VERSION 5.7 ;
BUSBITCHARS "[]" ;
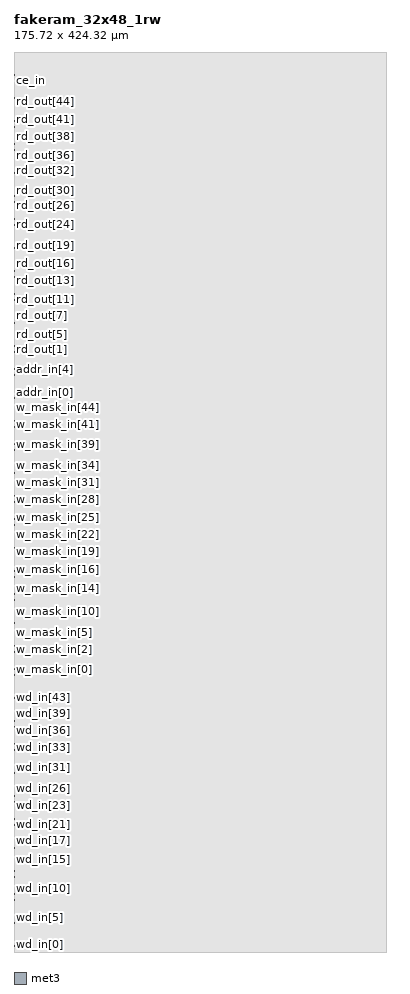
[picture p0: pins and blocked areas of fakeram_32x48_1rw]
MACRO fakeram_32x48_1rw
  FOREIGN fakeram_32x48_1rw 0 0 ;
  SYMMETRY X Y R90 ;
  SIZE 175.720 BY 424.320 ;
  CLASS BLOCK ;
  PIN wd_in[0]
    DIRECTION INPUT ;
    USE SIGNAL ;
    SHAPE ABUTMENT ;
    PORT
      LAYER met3 ;
      RECT 0.000 2.720 0.170 2.890 ;
    END
  END wd_in[0]
  PIN wd_in[1]
    DIRECTION INPUT ;
    USE SIGNAL ;
    SHAPE ABUTMENT ;
    PORT
      LAYER met3 ;
      RECT 0.000 5.440 0.170 5.610 ;
    END
  END wd_in[1]
  PIN wd_in[2]
    DIRECTION INPUT ;
    USE SIGNAL ;
    SHAPE ABUTMENT ;
    PORT
      LAYER met3 ;
      RECT 0.000 8.160 0.170 8.330 ;
    END
  END wd_in[2]
  PIN wd_in[3]
    DIRECTION INPUT ;
    USE SIGNAL ;
    SHAPE ABUTMENT ;
    PORT
      LAYER met3 ;
      RECT 0.000 10.880 0.170 11.050 ;
    END
  END wd_in[3]
  PIN wd_in[4]
    DIRECTION INPUT ;
    USE SIGNAL ;
    SHAPE ABUTMENT ;
    PORT
      LAYER met3 ;
      RECT 0.000 13.600 0.170 13.770 ;
    END
  END wd_in[4]
  PIN wd_in[5]
    DIRECTION INPUT ;
    USE SIGNAL ;
    SHAPE ABUTMENT ;
    PORT
      LAYER met3 ;
      RECT 0.000 16.320 0.170 16.490 ;
    END
  END wd_in[5]
  PIN wd_in[6]
    DIRECTION INPUT ;
    USE SIGNAL ;
    SHAPE ABUTMENT ;
    PORT
      LAYER met3 ;
      RECT 0.000 19.040 0.170 19.210 ;
    END
  END wd_in[6]
  PIN wd_in[7]
    DIRECTION INPUT ;
    USE SIGNAL ;
    SHAPE ABUTMENT ;
    PORT
      LAYER met3 ;
      RECT 0.000 21.760 0.170 21.930 ;
    END
  END wd_in[7]
  PIN wd_in[8]
    DIRECTION INPUT ;
    USE SIGNAL ;
    SHAPE ABUTMENT ;
    PORT
      LAYER met3 ;
      RECT 0.000 24.480 0.170 24.650 ;
    END
  END wd_in[8]
  PIN wd_in[9]
    DIRECTION INPUT ;
    USE SIGNAL ;
    SHAPE ABUTMENT ;
    PORT
      LAYER met3 ;
      RECT 0.000 27.200 0.170 27.370 ;
    END
  END wd_in[9]
  PIN wd_in[10]
    DIRECTION INPUT ;
    USE SIGNAL ;
    SHAPE ABUTMENT ;
    PORT
      LAYER met3 ;
      RECT 0.000 29.920 0.170 30.090 ;
    END
  END wd_in[10]
  PIN wd_in[11]
    DIRECTION INPUT ;
    USE SIGNAL ;
    SHAPE ABUTMENT ;
    PORT
      LAYER met3 ;
      RECT 0.000 32.640 0.170 32.810 ;
    END
  END wd_in[11]
  PIN wd_in[12]
    DIRECTION INPUT ;
    USE SIGNAL ;
    SHAPE ABUTMENT ;
    PORT
      LAYER met3 ;
      RECT 0.000 35.360 0.170 35.530 ;
    END
  END wd_in[12]
  PIN wd_in[13]
    DIRECTION INPUT ;
    USE SIGNAL ;
    SHAPE ABUTMENT ;
    PORT
      LAYER met3 ;
      RECT 0.000 38.080 0.170 38.250 ;
    END
  END wd_in[13]
  PIN wd_in[14]
    DIRECTION INPUT ;
    USE SIGNAL ;
    SHAPE ABUTMENT ;
    PORT
      LAYER met3 ;
      RECT 0.000 40.800 0.170 40.970 ;
    END
  END wd_in[14]
  PIN wd_in[15]
    DIRECTION INPUT ;
    USE SIGNAL ;
    SHAPE ABUTMENT ;
    PORT
      LAYER met3 ;
      RECT 0.000 43.520 0.170 43.690 ;
    END
  END wd_in[15]
  PIN wd_in[16]
    DIRECTION INPUT ;
    USE SIGNAL ;
    SHAPE ABUTMENT ;
    PORT
      LAYER met3 ;
      RECT 0.000 46.240 0.170 46.410 ;
    END
  END wd_in[16]
  PIN wd_in[17]
    DIRECTION INPUT ;
    USE SIGNAL ;
    SHAPE ABUTMENT ;
    PORT
      LAYER met3 ;
      RECT 0.000 48.960 0.170 49.130 ;
    END
  END wd_in[17]
  PIN wd_in[18]
    DIRECTION INPUT ;
    USE SIGNAL ;
    SHAPE ABUTMENT ;
    PORT
      LAYER met3 ;
      RECT 0.000 51.680 0.170 51.850 ;
    END
  END wd_in[18]
  PIN wd_in[19]
    DIRECTION INPUT ;
    USE SIGNAL ;
    SHAPE ABUTMENT ;
    PORT
      LAYER met3 ;
      RECT 0.000 54.400 0.170 54.570 ;
    END
  END wd_in[19]
  PIN wd_in[20]
    DIRECTION INPUT ;
    USE SIGNAL ;
    SHAPE ABUTMENT ;
    PORT
      LAYER met3 ;
      RECT 0.000 57.120 0.170 57.290 ;
    END
  END wd_in[20]
  PIN wd_in[21]
    DIRECTION INPUT ;
    USE SIGNAL ;
    SHAPE ABUTMENT ;
    PORT
      LAYER met3 ;
      RECT 0.000 59.840 0.170 60.010 ;
    END
  END wd_in[21]
  PIN wd_in[22]
    DIRECTION INPUT ;
    USE SIGNAL ;
    SHAPE ABUTMENT ;
    PORT
      LAYER met3 ;
      RECT 0.000 62.560 0.170 62.730 ;
    END
  END wd_in[22]
  PIN wd_in[23]
    DIRECTION INPUT ;
    USE SIGNAL ;
    SHAPE ABUTMENT ;
    PORT
      LAYER met3 ;
      RECT 0.000 65.280 0.170 65.450 ;
    END
  END wd_in[23]
  PIN wd_in[24]
    DIRECTION INPUT ;
    USE SIGNAL ;
    SHAPE ABUTMENT ;
    PORT
      LAYER met3 ;
      RECT 0.000 68.000 0.170 68.170 ;
    END
  END wd_in[24]
  PIN wd_in[25]
    DIRECTION INPUT ;
    USE SIGNAL ;
    SHAPE ABUTMENT ;
    PORT
      LAYER met3 ;
      RECT 0.000 70.720 0.170 70.890 ;
    END
  END wd_in[25]
  PIN wd_in[26]
    DIRECTION INPUT ;
    USE SIGNAL ;
    SHAPE ABUTMENT ;
    PORT
      LAYER met3 ;
      RECT 0.000 73.440 0.170 73.610 ;
    END
  END wd_in[26]
  PIN wd_in[27]
    DIRECTION INPUT ;
    USE SIGNAL ;
    SHAPE ABUTMENT ;
    PORT
      LAYER met3 ;
      RECT 0.000 76.160 0.170 76.330 ;
    END
  END wd_in[27]
  PIN wd_in[28]
    DIRECTION INPUT ;
    USE SIGNAL ;
    SHAPE ABUTMENT ;
    PORT
      LAYER met3 ;
      RECT 0.000 78.880 0.170 79.050 ;
    END
  END wd_in[28]
  PIN wd_in[29]
    DIRECTION INPUT ;
    USE SIGNAL ;
    SHAPE ABUTMENT ;
    PORT
      LAYER met3 ;
      RECT 0.000 81.600 0.170 81.770 ;
    END
  END wd_in[29]
  PIN wd_in[30]
    DIRECTION INPUT ;
    USE SIGNAL ;
    SHAPE ABUTMENT ;
    PORT
      LAYER met3 ;
      RECT 0.000 84.320 0.170 84.490 ;
    END
  END wd_in[30]
  PIN wd_in[31]
    DIRECTION INPUT ;
    USE SIGNAL ;
    SHAPE ABUTMENT ;
    PORT
      LAYER met3 ;
      RECT 0.000 87.040 0.170 87.210 ;
    END
  END wd_in[31]
  PIN wd_in[32]
    DIRECTION INPUT ;
    USE SIGNAL ;
    SHAPE ABUTMENT ;
    PORT
      LAYER met3 ;
      RECT 0.000 89.760 0.170 89.930 ;
    END
  END wd_in[32]
  PIN wd_in[33]
    DIRECTION INPUT ;
    USE SIGNAL ;
    SHAPE ABUTMENT ;
    PORT
      LAYER met3 ;
      RECT 0.000 92.480 0.170 92.650 ;
    END
  END wd_in[33]
  PIN wd_in[34]
    DIRECTION INPUT ;
    USE SIGNAL ;
    SHAPE ABUTMENT ;
    PORT
      LAYER met3 ;
      RECT 0.000 95.200 0.170 95.370 ;
    END
  END wd_in[34]
  PIN wd_in[35]
    DIRECTION INPUT ;
    USE SIGNAL ;
    SHAPE ABUTMENT ;
    PORT
      LAYER met3 ;
      RECT 0.000 97.920 0.170 98.090 ;
    END
  END wd_in[35]
  PIN wd_in[36]
    DIRECTION INPUT ;
    USE SIGNAL ;
    SHAPE ABUTMENT ;
    PORT
      LAYER met3 ;
      RECT 0.000 100.640 0.170 100.810 ;
    END
  END wd_in[36]
  PIN wd_in[37]
    DIRECTION INPUT ;
    USE SIGNAL ;
    SHAPE ABUTMENT ;
    PORT
      LAYER met3 ;
      RECT 0.000 103.360 0.170 103.530 ;
    END
  END wd_in[37]
  PIN wd_in[38]
    DIRECTION INPUT ;
    USE SIGNAL ;
    SHAPE ABUTMENT ;
    PORT
      LAYER met3 ;
      RECT 0.000 106.080 0.170 106.250 ;
    END
  END wd_in[38]
  PIN wd_in[39]
    DIRECTION INPUT ;
    USE SIGNAL ;
    SHAPE ABUTMENT ;
    PORT
      LAYER met3 ;
      RECT 0.000 108.800 0.170 108.970 ;
    END
  END wd_in[39]
  PIN wd_in[40]
    DIRECTION INPUT ;
    USE SIGNAL ;
    SHAPE ABUTMENT ;
    PORT
      LAYER met3 ;
      RECT 0.000 111.520 0.170 111.690 ;
    END
  END wd_in[40]
  PIN wd_in[41]
    DIRECTION INPUT ;
    USE SIGNAL ;
    SHAPE ABUTMENT ;
    PORT
      LAYER met3 ;
      RECT 0.000 114.240 0.170 114.410 ;
    END
  END wd_in[41]
  PIN wd_in[42]
    DIRECTION INPUT ;
    USE SIGNAL ;
    SHAPE ABUTMENT ;
    PORT
      LAYER met3 ;
      RECT 0.000 116.960 0.170 117.130 ;
    END
  END wd_in[42]
  PIN wd_in[43]
    DIRECTION INPUT ;
    USE SIGNAL ;
    SHAPE ABUTMENT ;
    PORT
      LAYER met3 ;
      RECT 0.000 119.680 0.170 119.850 ;
    END
  END wd_in[43]
  PIN wd_in[44]
    DIRECTION INPUT ;
    USE SIGNAL ;
    SHAPE ABUTMENT ;
    PORT
      LAYER met3 ;
      RECT 0.000 122.400 0.170 122.570 ;
    END
  END wd_in[44]
  PIN wd_in[45]
    DIRECTION INPUT ;
    USE SIGNAL ;
    SHAPE ABUTMENT ;
    PORT
      LAYER met3 ;
      RECT 0.000 125.120 0.170 125.290 ;
    END
  END wd_in[45]
  PIN wd_in[46]
    DIRECTION INPUT ;
    USE SIGNAL ;
    SHAPE ABUTMENT ;
    PORT
      LAYER met3 ;
      RECT 0.000 127.840 0.170 128.010 ;
    END
  END wd_in[46]
  PIN wd_in[47]
    DIRECTION INPUT ;
    USE SIGNAL ;
    SHAPE ABUTMENT ;
    PORT
      LAYER met3 ;
      RECT 0.000 130.560 0.170 130.730 ;
    END
  END wd_in[47]
  PIN w_mask_in[0]
    DIRECTION INPUT ;
    USE SIGNAL ;
    SHAPE ABUTMENT ;
    PORT
      LAYER met3 ;
      RECT 0.000 133.280 0.170 133.450 ;
    END
  END w_mask_in[0]
  PIN w_mask_in[1]
    DIRECTION INPUT ;
    USE SIGNAL ;
    SHAPE ABUTMENT ;
    PORT
      LAYER met3 ;
      RECT 0.000 136.000 0.170 136.170 ;
    END
  END w_mask_in[1]
  PIN w_mask_in[2]
    DIRECTION INPUT ;
    USE SIGNAL ;
    SHAPE ABUTMENT ;
    PORT
      LAYER met3 ;
      RECT 0.000 138.720 0.170 138.890 ;
    END
  END w_mask_in[2]
  PIN w_mask_in[3]
    DIRECTION INPUT ;
    USE SIGNAL ;
    SHAPE ABUTMENT ;
    PORT
      LAYER met3 ;
      RECT 0.000 141.440 0.170 141.610 ;
    END
  END w_mask_in[3]
  PIN w_mask_in[4]
    DIRECTION INPUT ;
    USE SIGNAL ;
    SHAPE ABUTMENT ;
    PORT
      LAYER met3 ;
      RECT 0.000 144.160 0.170 144.330 ;
    END
  END w_mask_in[4]
  PIN w_mask_in[5]
    DIRECTION INPUT ;
    USE SIGNAL ;
    SHAPE ABUTMENT ;
    PORT
      LAYER met3 ;
      RECT 0.000 146.880 0.170 147.050 ;
    END
  END w_mask_in[5]
  PIN w_mask_in[6]
    DIRECTION INPUT ;
    USE SIGNAL ;
    SHAPE ABUTMENT ;
    PORT
      LAYER met3 ;
      RECT 0.000 149.600 0.170 149.770 ;
    END
  END w_mask_in[6]
  PIN w_mask_in[7]
    DIRECTION INPUT ;
    USE SIGNAL ;
    SHAPE ABUTMENT ;
    PORT
      LAYER met3 ;
      RECT 0.000 152.320 0.170 152.490 ;
    END
  END w_mask_in[7]
  PIN w_mask_in[8]
    DIRECTION INPUT ;
    USE SIGNAL ;
    SHAPE ABUTMENT ;
    PORT
      LAYER met3 ;
      RECT 0.000 155.040 0.170 155.210 ;
    END
  END w_mask_in[8]
  PIN w_mask_in[9]
    DIRECTION INPUT ;
    USE SIGNAL ;
    SHAPE ABUTMENT ;
    PORT
      LAYER met3 ;
      RECT 0.000 157.760 0.170 157.930 ;
    END
  END w_mask_in[9]
  PIN w_mask_in[10]
    DIRECTION INPUT ;
    USE SIGNAL ;
    SHAPE ABUTMENT ;
    PORT
      LAYER met3 ;
      RECT 0.000 160.480 0.170 160.650 ;
    END
  END w_mask_in[10]
  PIN w_mask_in[11]
    DIRECTION INPUT ;
    USE SIGNAL ;
    SHAPE ABUTMENT ;
    PORT
      LAYER met3 ;
      RECT 0.000 163.200 0.170 163.370 ;
    END
  END w_mask_in[11]
  PIN w_mask_in[12]
    DIRECTION INPUT ;
    USE SIGNAL ;
    SHAPE ABUTMENT ;
    PORT
      LAYER met3 ;
      RECT 0.000 165.920 0.170 166.090 ;
    END
  END w_mask_in[12]
  PIN w_mask_in[13]
    DIRECTION INPUT ;
    USE SIGNAL ;
    SHAPE ABUTMENT ;
    PORT
      LAYER met3 ;
      RECT 0.000 168.640 0.170 168.810 ;
    END
  END w_mask_in[13]
  PIN w_mask_in[14]
    DIRECTION INPUT ;
    USE SIGNAL ;
    SHAPE ABUTMENT ;
    PORT
      LAYER met3 ;
      RECT 0.000 171.360 0.170 171.530 ;
    END
  END w_mask_in[14]
  PIN w_mask_in[15]
    DIRECTION INPUT ;
    USE SIGNAL ;
    SHAPE ABUTMENT ;
    PORT
      LAYER met3 ;
      RECT 0.000 174.080 0.170 174.250 ;
    END
  END w_mask_in[15]
  PIN w_mask_in[16]
    DIRECTION INPUT ;
    USE SIGNAL ;
    SHAPE ABUTMENT ;
    PORT
      LAYER met3 ;
      RECT 0.000 176.800 0.170 176.970 ;
    END
  END w_mask_in[16]
  PIN w_mask_in[17]
    DIRECTION INPUT ;
    USE SIGNAL ;
    SHAPE ABUTMENT ;
    PORT
      LAYER met3 ;
      RECT 0.000 179.520 0.170 179.690 ;
    END
  END w_mask_in[17]
  PIN w_mask_in[18]
    DIRECTION INPUT ;
    USE SIGNAL ;
    SHAPE ABUTMENT ;
    PORT
      LAYER met3 ;
      RECT 0.000 182.240 0.170 182.410 ;
    END
  END w_mask_in[18]
  PIN w_mask_in[19]
    DIRECTION INPUT ;
    USE SIGNAL ;
    SHAPE ABUTMENT ;
    PORT
      LAYER met3 ;
      RECT 0.000 184.960 0.170 185.130 ;
    END
  END w_mask_in[19]
  PIN w_mask_in[20]
    DIRECTION INPUT ;
    USE SIGNAL ;
    SHAPE ABUTMENT ;
    PORT
      LAYER met3 ;
      RECT 0.000 187.680 0.170 187.850 ;
    END
  END w_mask_in[20]
  PIN w_mask_in[21]
    DIRECTION INPUT ;
    USE SIGNAL ;
    SHAPE ABUTMENT ;
    PORT
      LAYER met3 ;
      RECT 0.000 190.400 0.170 190.570 ;
    END
  END w_mask_in[21]
  PIN w_mask_in[22]
    DIRECTION INPUT ;
    USE SIGNAL ;
    SHAPE ABUTMENT ;
    PORT
      LAYER met3 ;
      RECT 0.000 193.120 0.170 193.290 ;
    END
  END w_mask_in[22]
  PIN w_mask_in[23]
    DIRECTION INPUT ;
    USE SIGNAL ;
    SHAPE ABUTMENT ;
    PORT
      LAYER met3 ;
      RECT 0.000 195.840 0.170 196.010 ;
    END
  END w_mask_in[23]
  PIN w_mask_in[24]
    DIRECTION INPUT ;
    USE SIGNAL ;
    SHAPE ABUTMENT ;
    PORT
      LAYER met3 ;
      RECT 0.000 198.560 0.170 198.730 ;
    END
  END w_mask_in[24]
  PIN w_mask_in[25]
    DIRECTION INPUT ;
    USE SIGNAL ;
    SHAPE ABUTMENT ;
    PORT
      LAYER met3 ;
      RECT 0.000 201.280 0.170 201.450 ;
    END
  END w_mask_in[25]
  PIN w_mask_in[26]
    DIRECTION INPUT ;
    USE SIGNAL ;
    SHAPE ABUTMENT ;
    PORT
      LAYER met3 ;
      RECT 0.000 204.000 0.170 204.170 ;
    END
  END w_mask_in[26]
  PIN w_mask_in[27]
    DIRECTION INPUT ;
    USE SIGNAL ;
    SHAPE ABUTMENT ;
    PORT
      LAYER met3 ;
      RECT 0.000 206.720 0.170 206.890 ;
    END
  END w_mask_in[27]
  PIN w_mask_in[28]
    DIRECTION INPUT ;
    USE SIGNAL ;
    SHAPE ABUTMENT ;
    PORT
      LAYER met3 ;
      RECT 0.000 209.440 0.170 209.610 ;
    END
  END w_mask_in[28]
  PIN w_mask_in[29]
    DIRECTION INPUT ;
    USE SIGNAL ;
    SHAPE ABUTMENT ;
    PORT
      LAYER met3 ;
      RECT 0.000 212.160 0.170 212.330 ;
    END
  END w_mask_in[29]
  PIN w_mask_in[30]
    DIRECTION INPUT ;
    USE SIGNAL ;
    SHAPE ABUTMENT ;
    PORT
      LAYER met3 ;
      RECT 0.000 214.880 0.170 215.050 ;
    END
  END w_mask_in[30]
  PIN w_mask_in[31]
    DIRECTION INPUT ;
    USE SIGNAL ;
    SHAPE ABUTMENT ;
    PORT
      LAYER met3 ;
      RECT 0.000 217.600 0.170 217.770 ;
    END
  END w_mask_in[31]
  PIN w_mask_in[32]
    DIRECTION INPUT ;
    USE SIGNAL ;
    SHAPE ABUTMENT ;
    PORT
      LAYER met3 ;
      RECT 0.000 220.320 0.170 220.490 ;
    END
  END w_mask_in[32]
  PIN w_mask_in[33]
    DIRECTION INPUT ;
    USE SIGNAL ;
    SHAPE ABUTMENT ;
    PORT
      LAYER met3 ;
      RECT 0.000 223.040 0.170 223.210 ;
    END
  END w_mask_in[33]
  PIN w_mask_in[34]
    DIRECTION INPUT ;
    USE SIGNAL ;
    SHAPE ABUTMENT ;
    PORT
      LAYER met3 ;
      RECT 0.000 225.760 0.170 225.930 ;
    END
  END w_mask_in[34]
  PIN w_mask_in[35]
    DIRECTION INPUT ;
    USE SIGNAL ;
    SHAPE ABUTMENT ;
    PORT
      LAYER met3 ;
      RECT 0.000 228.480 0.170 228.650 ;
    END
  END w_mask_in[35]
  PIN w_mask_in[36]
    DIRECTION INPUT ;
    USE SIGNAL ;
    SHAPE ABUTMENT ;
    PORT
      LAYER met3 ;
      RECT 0.000 231.200 0.170 231.370 ;
    END
  END w_mask_in[36]
  PIN w_mask_in[37]
    DIRECTION INPUT ;
    USE SIGNAL ;
    SHAPE ABUTMENT ;
    PORT
      LAYER met3 ;
      RECT 0.000 233.920 0.170 234.090 ;
    END
  END w_mask_in[37]
  PIN w_mask_in[38]
    DIRECTION INPUT ;
    USE SIGNAL ;
    SHAPE ABUTMENT ;
    PORT
      LAYER met3 ;
      RECT 0.000 236.640 0.170 236.810 ;
    END
  END w_mask_in[38]
  PIN w_mask_in[39]
    DIRECTION INPUT ;
    USE SIGNAL ;
    SHAPE ABUTMENT ;
    PORT
      LAYER met3 ;
      RECT 0.000 239.360 0.170 239.530 ;
    END
  END w_mask_in[39]
  PIN w_mask_in[40]
    DIRECTION INPUT ;
    USE SIGNAL ;
    SHAPE ABUTMENT ;
    PORT
      LAYER met3 ;
      RECT 0.000 242.080 0.170 242.250 ;
    END
  END w_mask_in[40]
  PIN w_mask_in[41]
    DIRECTION INPUT ;
    USE SIGNAL ;
    SHAPE ABUTMENT ;
    PORT
      LAYER met3 ;
      RECT 0.000 244.800 0.170 244.970 ;
    END
  END w_mask_in[41]
  PIN w_mask_in[42]
    DIRECTION INPUT ;
    USE SIGNAL ;
    SHAPE ABUTMENT ;
    PORT
      LAYER met3 ;
      RECT 0.000 247.520 0.170 247.690 ;
    END
  END w_mask_in[42]
  PIN w_mask_in[43]
    DIRECTION INPUT ;
    USE SIGNAL ;
    SHAPE ABUTMENT ;
    PORT
      LAYER met3 ;
      RECT 0.000 250.240 0.170 250.410 ;
    END
  END w_mask_in[43]
  PIN w_mask_in[44]
    DIRECTION INPUT ;
    USE SIGNAL ;
    SHAPE ABUTMENT ;
    PORT
      LAYER met3 ;
      RECT 0.000 252.960 0.170 253.130 ;
    END
  END w_mask_in[44]
  PIN w_mask_in[45]
    DIRECTION INPUT ;
    USE SIGNAL ;
    SHAPE ABUTMENT ;
    PORT
      LAYER met3 ;
      RECT 0.000 255.680 0.170 255.850 ;
    END
  END w_mask_in[45]
  PIN w_mask_in[46]
    DIRECTION INPUT ;
    USE SIGNAL ;
    SHAPE ABUTMENT ;
    PORT
      LAYER met3 ;
      RECT 0.000 258.400 0.170 258.570 ;
    END
  END w_mask_in[46]
  PIN w_mask_in[47]
    DIRECTION INPUT ;
    USE SIGNAL ;
    SHAPE ABUTMENT ;
    PORT
      LAYER met3 ;
      RECT 0.000 261.120 0.170 261.290 ;
    END
  END w_mask_in[47]
  PIN addr_in[0]
    DIRECTION INPUT ;
    USE SIGNAL ;
    SHAPE ABUTMENT ;
    PORT
      LAYER met3 ;
      RECT 0.000 263.840 0.170 264.010 ;
    END
  END addr_in[0]
  PIN addr_in[1]
    DIRECTION INPUT ;
    USE SIGNAL ;
    SHAPE ABUTMENT ;
    PORT
      LAYER met3 ;
      RECT 0.000 266.560 0.170 266.730 ;
    END
  END addr_in[1]
  PIN addr_in[2]
    DIRECTION INPUT ;
    USE SIGNAL ;
    SHAPE ABUTMENT ;
    PORT
      LAYER met3 ;
      RECT 0.000 269.280 0.170 269.450 ;
    END
  END addr_in[2]
  PIN addr_in[3]
    DIRECTION INPUT ;
    USE SIGNAL ;
    SHAPE ABUTMENT ;
    PORT
      LAYER met3 ;
      RECT 0.000 272.000 0.170 272.170 ;
    END
  END addr_in[3]
  PIN addr_in[4]
    DIRECTION INPUT ;
    USE SIGNAL ;
    SHAPE ABUTMENT ;
    PORT
      LAYER met3 ;
      RECT 0.000 274.720 0.170 274.890 ;
    END
  END addr_in[4]
  PIN rd_out[0]
    DIRECTION OUTPUT ;
    USE SIGNAL ;
    SHAPE ABUTMENT ;
    PORT
      LAYER met3 ;
      RECT 0.000 277.440 0.170 277.610 ;
    END
  END rd_out[0]
  PIN rd_out[1]
    DIRECTION OUTPUT ;
    USE SIGNAL ;
    SHAPE ABUTMENT ;
    PORT
      LAYER met3 ;
      RECT 0.000 280.160 0.170 280.330 ;
    END
  END rd_out[1]
  PIN rd_out[2]
    DIRECTION OUTPUT ;
    USE SIGNAL ;
    SHAPE ABUTMENT ;
    PORT
      LAYER met3 ;
      RECT 0.000 282.880 0.170 283.050 ;
    END
  END rd_out[2]
  PIN rd_out[3]
    DIRECTION OUTPUT ;
    USE SIGNAL ;
    SHAPE ABUTMENT ;
    PORT
      LAYER met3 ;
      RECT 0.000 285.600 0.170 285.770 ;
    END
  END rd_out[3]
  PIN rd_out[4]
    DIRECTION OUTPUT ;
    USE SIGNAL ;
    SHAPE ABUTMENT ;
    PORT
      LAYER met3 ;
      RECT 0.000 288.320 0.170 288.490 ;
    END
  END rd_out[4]
  PIN rd_out[5]
    DIRECTION OUTPUT ;
    USE SIGNAL ;
    SHAPE ABUTMENT ;
    PORT
      LAYER met3 ;
      RECT 0.000 291.040 0.170 291.210 ;
    END
  END rd_out[5]
  PIN rd_out[6]
    DIRECTION OUTPUT ;
    USE SIGNAL ;
    SHAPE ABUTMENT ;
    PORT
      LAYER met3 ;
      RECT 0.000 293.760 0.170 293.930 ;
    END
  END rd_out[6]
  PIN rd_out[7]
    DIRECTION OUTPUT ;
    USE SIGNAL ;
    SHAPE ABUTMENT ;
    PORT
      LAYER met3 ;
      RECT 0.000 296.480 0.170 296.650 ;
    END
  END rd_out[7]
  PIN rd_out[8]
    DIRECTION OUTPUT ;
    USE SIGNAL ;
    SHAPE ABUTMENT ;
    PORT
      LAYER met3 ;
      RECT 0.000 299.200 0.170 299.370 ;
    END
  END rd_out[8]
  PIN rd_out[9]
    DIRECTION OUTPUT ;
    USE SIGNAL ;
    SHAPE ABUTMENT ;
    PORT
      LAYER met3 ;
      RECT 0.000 301.920 0.170 302.090 ;
    END
  END rd_out[9]
  PIN rd_out[10]
    DIRECTION OUTPUT ;
    USE SIGNAL ;
    SHAPE ABUTMENT ;
    PORT
      LAYER met3 ;
      RECT 0.000 304.640 0.170 304.810 ;
    END
  END rd_out[10]
  PIN rd_out[11]
    DIRECTION OUTPUT ;
    USE SIGNAL ;
    SHAPE ABUTMENT ;
    PORT
      LAYER met3 ;
      RECT 0.000 307.360 0.170 307.530 ;
    END
  END rd_out[11]
  PIN rd_out[12]
    DIRECTION OUTPUT ;
    USE SIGNAL ;
    SHAPE ABUTMENT ;
    PORT
      LAYER met3 ;
      RECT 0.000 310.080 0.170 310.250 ;
    END
  END rd_out[12]
  PIN rd_out[13]
    DIRECTION OUTPUT ;
    USE SIGNAL ;
    SHAPE ABUTMENT ;
    PORT
      LAYER met3 ;
      RECT 0.000 312.800 0.170 312.970 ;
    END
  END rd_out[13]
  PIN rd_out[14]
    DIRECTION OUTPUT ;
    USE SIGNAL ;
    SHAPE ABUTMENT ;
    PORT
      LAYER met3 ;
      RECT 0.000 315.520 0.170 315.690 ;
    END
  END rd_out[14]
  PIN rd_out[15]
    DIRECTION OUTPUT ;
    USE SIGNAL ;
    SHAPE ABUTMENT ;
    PORT
      LAYER met3 ;
      RECT 0.000 318.240 0.170 318.410 ;
    END
  END rd_out[15]
  PIN rd_out[16]
    DIRECTION OUTPUT ;
    USE SIGNAL ;
    SHAPE ABUTMENT ;
    PORT
      LAYER met3 ;
      RECT 0.000 320.960 0.170 321.130 ;
    END
  END rd_out[16]
  PIN rd_out[17]
    DIRECTION OUTPUT ;
    USE SIGNAL ;
    SHAPE ABUTMENT ;
    PORT
      LAYER met3 ;
      RECT 0.000 323.680 0.170 323.850 ;
    END
  END rd_out[17]
  PIN rd_out[18]
    DIRECTION OUTPUT ;
    USE SIGNAL ;
    SHAPE ABUTMENT ;
    PORT
      LAYER met3 ;
      RECT 0.000 326.400 0.170 326.570 ;
    END
  END rd_out[18]
  PIN rd_out[19]
    DIRECTION OUTPUT ;
    USE SIGNAL ;
    SHAPE ABUTMENT ;
    PORT
      LAYER met3 ;
      RECT 0.000 329.120 0.170 329.290 ;
    END
  END rd_out[19]
  PIN rd_out[20]
    DIRECTION OUTPUT ;
    USE SIGNAL ;
    SHAPE ABUTMENT ;
    PORT
      LAYER met3 ;
      RECT 0.000 331.840 0.170 332.010 ;
    END
  END rd_out[20]
  PIN rd_out[21]
    DIRECTION OUTPUT ;
    USE SIGNAL ;
    SHAPE ABUTMENT ;
    PORT
      LAYER met3 ;
      RECT 0.000 334.560 0.170 334.730 ;
    END
  END rd_out[21]
  PIN rd_out[22]
    DIRECTION OUTPUT ;
    USE SIGNAL ;
    SHAPE ABUTMENT ;
    PORT
      LAYER met3 ;
      RECT 0.000 337.280 0.170 337.450 ;
    END
  END rd_out[22]
  PIN rd_out[23]
    DIRECTION OUTPUT ;
    USE SIGNAL ;
    SHAPE ABUTMENT ;
    PORT
      LAYER met3 ;
      RECT 0.000 340.000 0.170 340.170 ;
    END
  END rd_out[23]
  PIN rd_out[24]
    DIRECTION OUTPUT ;
    USE SIGNAL ;
    SHAPE ABUTMENT ;
    PORT
      LAYER met3 ;
      RECT 0.000 342.720 0.170 342.890 ;
    END
  END rd_out[24]
  PIN rd_out[25]
    DIRECTION OUTPUT ;
    USE SIGNAL ;
    SHAPE ABUTMENT ;
    PORT
      LAYER met3 ;
      RECT 0.000 345.440 0.170 345.610 ;
    END
  END rd_out[25]
  PIN rd_out[26]
    DIRECTION OUTPUT ;
    USE SIGNAL ;
    SHAPE ABUTMENT ;
    PORT
      LAYER met3 ;
      RECT 0.000 348.160 0.170 348.330 ;
    END
  END rd_out[26]
  PIN rd_out[27]
    DIRECTION OUTPUT ;
    USE SIGNAL ;
    SHAPE ABUTMENT ;
    PORT
      LAYER met3 ;
      RECT 0.000 350.880 0.170 351.050 ;
    END
  END rd_out[27]
  PIN rd_out[28]
    DIRECTION OUTPUT ;
    USE SIGNAL ;
    SHAPE ABUTMENT ;
    PORT
      LAYER met3 ;
      RECT 0.000 353.600 0.170 353.770 ;
    END
  END rd_out[28]
  PIN rd_out[29]
    DIRECTION OUTPUT ;
    USE SIGNAL ;
    SHAPE ABUTMENT ;
    PORT
      LAYER met3 ;
      RECT 0.000 356.320 0.170 356.490 ;
    END
  END rd_out[29]
  PIN rd_out[30]
    DIRECTION OUTPUT ;
    USE SIGNAL ;
    SHAPE ABUTMENT ;
    PORT
      LAYER met3 ;
      RECT 0.000 359.040 0.170 359.210 ;
    END
  END rd_out[30]
  PIN rd_out[31]
    DIRECTION OUTPUT ;
    USE SIGNAL ;
    SHAPE ABUTMENT ;
    PORT
      LAYER met3 ;
      RECT 0.000 361.760 0.170 361.930 ;
    END
  END rd_out[31]
  PIN rd_out[32]
    DIRECTION OUTPUT ;
    USE SIGNAL ;
    SHAPE ABUTMENT ;
    PORT
      LAYER met3 ;
      RECT 0.000 364.480 0.170 364.650 ;
    END
  END rd_out[32]
  PIN rd_out[33]
    DIRECTION OUTPUT ;
    USE SIGNAL ;
    SHAPE ABUTMENT ;
    PORT
      LAYER met3 ;
      RECT 0.000 367.200 0.170 367.370 ;
    END
  END rd_out[33]
  PIN rd_out[34]
    DIRECTION OUTPUT ;
    USE SIGNAL ;
    SHAPE ABUTMENT ;
    PORT
      LAYER met3 ;
      RECT 0.000 369.920 0.170 370.090 ;
    END
  END rd_out[34]
  PIN rd_out[35]
    DIRECTION OUTPUT ;
    USE SIGNAL ;
    SHAPE ABUTMENT ;
    PORT
      LAYER met3 ;
      RECT 0.000 372.640 0.170 372.810 ;
    END
  END rd_out[35]
  PIN rd_out[36]
    DIRECTION OUTPUT ;
    USE SIGNAL ;
    SHAPE ABUTMENT ;
    PORT
      LAYER met3 ;
      RECT 0.000 375.360 0.170 375.530 ;
    END
  END rd_out[36]
  PIN rd_out[37]
    DIRECTION OUTPUT ;
    USE SIGNAL ;
    SHAPE ABUTMENT ;
    PORT
      LAYER met3 ;
      RECT 0.000 378.080 0.170 378.250 ;
    END
  END rd_out[37]
  PIN rd_out[38]
    DIRECTION OUTPUT ;
    USE SIGNAL ;
    SHAPE ABUTMENT ;
    PORT
      LAYER met3 ;
      RECT 0.000 380.800 0.170 380.970 ;
    END
  END rd_out[38]
  PIN rd_out[39]
    DIRECTION OUTPUT ;
    USE SIGNAL ;
    SHAPE ABUTMENT ;
    PORT
      LAYER met3 ;
      RECT 0.000 383.520 0.170 383.690 ;
    END
  END rd_out[39]
  PIN rd_out[40]
    DIRECTION OUTPUT ;
    USE SIGNAL ;
    SHAPE ABUTMENT ;
    PORT
      LAYER met3 ;
      RECT 0.000 386.240 0.170 386.410 ;
    END
  END rd_out[40]
  PIN rd_out[41]
    DIRECTION OUTPUT ;
    USE SIGNAL ;
    SHAPE ABUTMENT ;
    PORT
      LAYER met3 ;
      RECT 0.000 388.960 0.170 389.130 ;
    END
  END rd_out[41]
  PIN rd_out[42]
    DIRECTION OUTPUT ;
    USE SIGNAL ;
    SHAPE ABUTMENT ;
    PORT
      LAYER met3 ;
      RECT 0.000 391.680 0.170 391.850 ;
    END
  END rd_out[42]
  PIN rd_out[43]
    DIRECTION OUTPUT ;
    USE SIGNAL ;
    SHAPE ABUTMENT ;
    PORT
      LAYER met3 ;
      RECT 0.000 394.400 0.170 394.570 ;
    END
  END rd_out[43]
  PIN rd_out[44]
    DIRECTION OUTPUT ;
    USE SIGNAL ;
    SHAPE ABUTMENT ;
    PORT
      LAYER met3 ;
      RECT 0.000 397.120 0.170 397.290 ;
    END
  END rd_out[44]
  PIN rd_out[45]
    DIRECTION OUTPUT ;
    USE SIGNAL ;
    SHAPE ABUTMENT ;
    PORT
      LAYER met3 ;
      RECT 0.000 399.840 0.170 400.010 ;
    END
  END rd_out[45]
  PIN rd_out[46]
    DIRECTION OUTPUT ;
    USE SIGNAL ;
    SHAPE ABUTMENT ;
    PORT
      LAYER met3 ;
      RECT 0.000 402.560 0.170 402.730 ;
    END
  END rd_out[46]
  PIN rd_out[47]
    DIRECTION OUTPUT ;
    USE SIGNAL ;
    SHAPE ABUTMENT ;
    PORT
      LAYER met3 ;
      RECT 0.000 405.280 0.170 405.450 ;
    END
  END rd_out[47]
  PIN clk
    DIRECTION INPUT ;
    USE SIGNAL ;
    SHAPE ABUTMENT ;
    PORT
      LAYER met3 ;
      RECT 0.000 408.000 0.170 408.170 ;
    END
  END clk
  PIN ce_in
    DIRECTION INPUT ;
    USE SIGNAL ;
    SHAPE ABUTMENT ;
    PORT
      LAYER met3 ;
      RECT 0.000 410.720 0.170 410.890 ;
    END
  END ce_in
  PIN we_in
    DIRECTION INPUT ;
    USE SIGNAL ;
    SHAPE ABUTMENT ;
    PORT
      LAYER met3 ;
      RECT 0.000 413.440 0.170 413.610 ;
    END
  END we_in
  OBS
    LAYER met1 ;
      RECT 0.000 0.000 175.720 424.320 ;
    LAYER met2 ;
      RECT 0.000 0.000 175.720 424.320 ;
    LAYER met3 ;
      RECT 0.000 0.000 175.720 424.320 ;
  END
END fakeram_32x48_1rw
END LIBRARY
